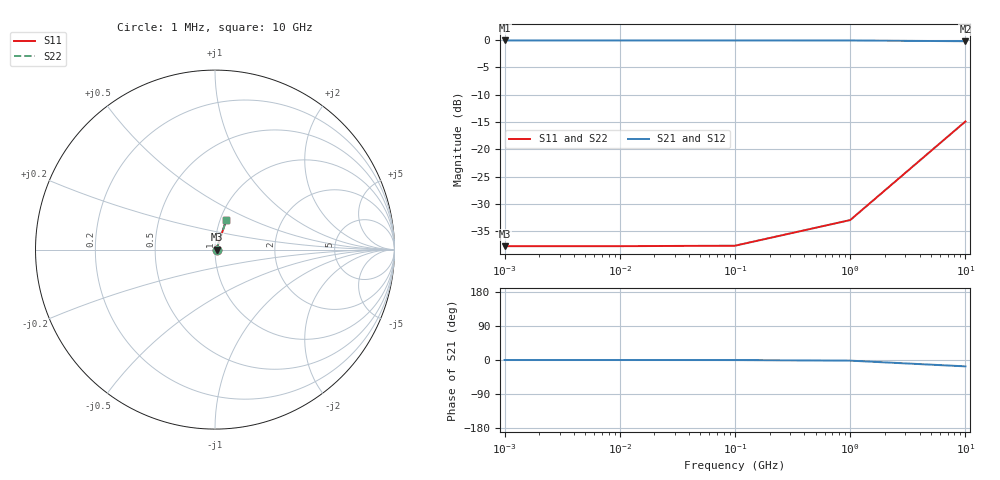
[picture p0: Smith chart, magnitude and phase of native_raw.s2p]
! Sonnet Data File
! From: em Version : 18.53-Lite
! From Project: project
! Data is NOT De-embedded
! Data File Written: 10/07/2026 08:33:05
!< HDATE 10/07/2026 08:33:05
!< MDATE 10/07/2026 08:33:05
# GHZ S RI R 50.00000
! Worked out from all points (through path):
!   5 points, 1 MHz to 10 GHz, reference 50 ohm
!   highest |S21| = -0.11 dB at 1 MHz (marker M1); lowest = -0.3 dB at 10 GHz (marker M2)
!   lowest |S11| = -37.7 dB at 1 MHz (marker M3), VSWR 1.03, Z = 51.3 + j0.00186 ohm
!   |S11| at or under -10 dB: start of sweep to end of sweep
!   |S22| runs from -37.7 to -14.9 dB; largest |S21 - S12| = 3.2e-12
0.001  0.013 1.81e-05  0.987 -2.94e-05  0.987 -2.94e-05  0.013 1.81e-05
0.01  0.013 0.00018  0.987 -0.000293  0.987 -0.000293  0.013 0.00018
0.1  0.013 0.0018  0.987 -0.00293  0.987 -0.00293  0.013 0.0018
1  0.0135 0.018  0.9864 -0.0293  0.9864 -0.0293  0.0135 0.018
10  0.0639 0.1675  0.9296 -0.2808  0.9296 -0.2808  0.0639 0.1675
